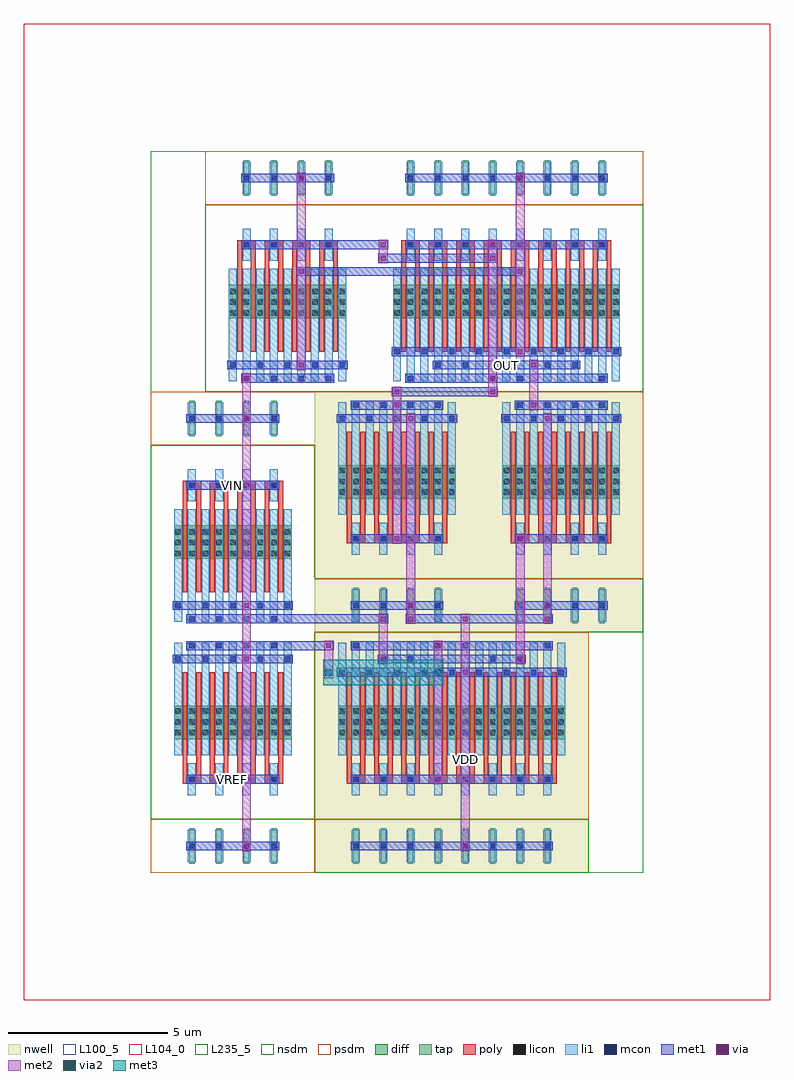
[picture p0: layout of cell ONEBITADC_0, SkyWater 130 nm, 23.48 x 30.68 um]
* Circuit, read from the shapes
.subckt ONEBITADC_0 OUT VDD VIN VREF
XM1 n1 VREF VSUBS VSUBS sky130_fd_pr__nfet_01v8 w=1.05 l=0.15 m=8
XM2 n2 VIN VSUBS VSUBS sky130_fd_pr__nfet_01v8 w=1.05 l=0.15 m=8
XM3 VSUBS n3 VSUBS VSUBS sky130_fd_pr__nfet_01v8 w=1.05 l=0.15 m=8
XM4 n3 n3 VSUBS VSUBS sky130_fd_pr__nfet_01v8 w=1.05 l=0.15 m=8
XM5 OUT n3 VSUBS VSUBS sky130_fd_pr__nfet_01v8 w=1.05 l=0.15 m=8
XM6 n1 n1 VDD VDD sky130_fd_pr__pfet_01v8 w=1.05 l=0.15 m=8
XM7 n3 n3 VDD VDD sky130_fd_pr__pfet_01v8 w=1.05 l=0.15 m=8
XM8 n2 n1 VDD VDD sky130_fd_pr__pfet_01v8 w=1.05 l=0.15 m=8
XM9 OUT n2 VDD VDD sky130_fd_pr__pfet_01v8 w=1.05 l=0.15 m=8
.ends

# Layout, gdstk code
from math import pi, radians
import gdstk
lib = gdstk.Library(unit=1e-6, precision=1e-09)
def R(c, l, rs):  # rectangles x0, y0, x1, y1
    for r in rs: c.add(gdstk.rectangle(r[:2], r[2:], *l))
def A(c, l, x, y, w, h, nx, ny, dx, dy):  # array of equal rectangles
    R(c, l, [(x+i*dx, y+j*dy, x+i*dx+w, y+j*dy+h) for i in range(nx) for j in range(ny)])
def P(c, l, *ps):  # polygons
    for p in ps: c.add(gdstk.Polygon(p, *l))
nwell = (64, 20)
diff = (65, 20)
tap = (65, 44)
poly = (66, 20)
licon = (66, 44)
li1 = (67, 20)
mcon = (67, 44)
met1 = (68, 20)
via = (68, 44)
met2 = (69, 20)
via2 = (69, 44)
met3 = (70, 20)
nsdm = (93, 44)
psdm = (94, 20)
L100_5 = (100, 5)
L104_0 = (104, 0)
L235_5 = (235, 5)

scm_nmos_38434623_x4_y1_ = lib.new_cell('SCM_NMOS_38434623_X4_Y1_1678970416_1678970418')
R(scm_nmos_38434623_x4_y1_, diff, [(0.735,2.31,7.865,3.36)])
A(scm_nmos_38434623_x4_y1_, tap, 1.205, 6.16, 0.17, 1.12, 8, 1, 0.86, 0)
A(scm_nmos_38434623_x4_y1_, poly, 1, 1.26, 0.15, 3.36, 16, 1, 0.43, 0)
A(scm_nmos_38434623_x4_y1_, poly, 1, 4.485, 0.58, 0.27, 8, 1, 0.86, 0)
A(scm_nmos_38434623_x4_y1_, licon, 0.775, 2.39, 0.17, 0.17, 3, 3, 0.43, 0.34)
A(scm_nmos_38434623_x4_y1_, licon, 1.635, 2.39, 0.17, 0.17, 3, 3, 0.43, 0.34)
A(scm_nmos_38434623_x4_y1_, licon, 2.495, 2.39, 0.17, 0.17, 3, 3, 0.43, 0.34)
A(scm_nmos_38434623_x4_y1_, licon, 3.355, 2.39, 0.17, 0.17, 3, 3, 0.43, 0.34)
A(scm_nmos_38434623_x4_y1_, licon, 4.215, 2.39, 0.17, 0.17, 3, 3, 0.43, 0.34)
A(scm_nmos_38434623_x4_y1_, licon, 5.075, 2.39, 0.17, 0.17, 3, 3, 0.43, 0.34)
A(scm_nmos_38434623_x4_y1_, licon, 5.935, 2.39, 0.17, 0.17, 3, 3, 0.43, 0.34)
A(scm_nmos_38434623_x4_y1_, licon, 6.795, 2.39, 0.17, 0.17, 3, 3, 0.43, 0.34)
A(scm_nmos_38434623_x4_y1_, licon, 1.205, 4.535, 0.17, 0.17, 8, 2, 0.86, 2.1)
A(scm_nmos_38434623_x4_y1_, li1, 0.735, 0.335, 0.25, 3.53, 17, 1, 0.43, 0)
A(scm_nmos_38434623_x4_y1_, li1, 1.165, 4.115, 0.25, 1.01, 8, 2, 0.86, 2.1)
A(scm_nmos_38434623_x4_y1_, mcon, 0.775, 1.175, 0.17, 0.17, 9, 1, 0.86, 0)
A(scm_nmos_38434623_x4_y1_, mcon, 1.205, 4.535, 0.17, 0.17, 8, 2, 0.86, 2.1)
R(scm_nmos_38434623_x4_y1_, mcon, [(1.205,0.335,1.375,0.505), (3.785,0.335,3.955,0.505), (4.645,0.335,4.815,0.505), (7.225,0.335,7.395,0.505), (2.065,0.755,2.235,0.925), (2.925,0.755,3.095,0.925), (5.505,0.755,5.675,0.925), (6.365,0.755,6.535,0.925)])
R(scm_nmos_38434623_x4_y1_, met1, [(1.12,0.28,7.48,0.56), (1.98,0.7,6.62,0.98), (0.69,1.12,7.91,1.4), (1.12,4.48,7.48,4.76), (1.12,6.58,7.48,6.86)])
R(scm_nmos_38434623_x4_y1_, via, [(3.795,0.345,3.945,0.495), (4.655,1.185,4.805,1.335), (3.795,4.545,3.945,4.695), (4.655,6.645,4.805,6.795)])
R(scm_nmos_38434623_x4_y1_, met2, [(3.73,0.26,4.01,4.78), (4.59,1.1,4.87,6.88)])
R(scm_nmos_38434623_x4_y1_, nsdm, [(0,0,8.6,5.88)])
R(scm_nmos_38434623_x4_y1_, psdm, [(0,5.88,8.6,7.56)])
R(scm_nmos_38434623_x4_y1_, L100_5, [(0,0,8.6,7.56)])

nmos_s_93094360_x4_y1_16 = lib.new_cell('NMOS_S_93094360_X4_Y1_1678970415_1678970418')
R(nmos_s_93094360_x4_y1_16, diff, [(0.735,2.31,4.425,3.36)])
A(nmos_s_93094360_x4_y1_16, tap, 1.205, 6.16, 0.17, 1.12, 4, 1, 0.86, 0)
A(nmos_s_93094360_x4_y1_16, poly, 1, 1.26, 0.15, 3.36, 8, 1, 0.43, 0)
A(nmos_s_93094360_x4_y1_16, poly, 1, 4.485, 0.58, 0.27, 4, 1, 0.86, 0)
A(nmos_s_93094360_x4_y1_16, licon, 0.775, 2.39, 0.17, 0.17, 3, 3, 0.43, 0.34)
A(nmos_s_93094360_x4_y1_16, licon, 1.635, 2.39, 0.17, 0.17, 3, 3, 0.43, 0.34)
A(nmos_s_93094360_x4_y1_16, licon, 2.495, 2.39, 0.17, 0.17, 3, 3, 0.43, 0.34)
A(nmos_s_93094360_x4_y1_16, licon, 3.355, 2.39, 0.17, 0.17, 3, 3, 0.43, 0.34)
A(nmos_s_93094360_x4_y1_16, licon, 1.205, 4.535, 0.17, 0.17, 4, 2, 0.86, 2.1)
A(nmos_s_93094360_x4_y1_16, li1, 0.735, 0.335, 0.25, 3.53, 9, 1, 0.43, 0)
A(nmos_s_93094360_x4_y1_16, li1, 1.165, 4.115, 0.25, 1.01, 4, 2, 0.86, 2.1)
A(nmos_s_93094360_x4_y1_16, mcon, 1.205, 0.335, 0.17, 0.17, 4, 2, 0.86, 4.2)
A(nmos_s_93094360_x4_y1_16, mcon, 0.775, 0.755, 0.17, 0.17, 5, 1, 0.86, 0)
A(nmos_s_93094360_x4_y1_16, mcon, 1.205, 6.635, 0.17, 0.17, 4, 1, 0.86, 0)
R(nmos_s_93094360_x4_y1_16, met1, [(1.12,0.28,4.04,0.56), (0.69,0.7,4.47,0.98), (1.12,4.48,4.04,4.76), (1.12,6.58,4.04,6.86)])
R(nmos_s_93094360_x4_y1_16, via, [(2.935,0.765,3.085,0.915), (2.935,6.645,3.085,6.795)])
R(nmos_s_93094360_x4_y1_16, met2, [(2.87,0.68,3.15,6.88)])
R(nmos_s_93094360_x4_y1_16, nsdm, [(0,0,5.16,5.88)])
R(nmos_s_93094360_x4_y1_16, psdm, [(0,5.88,5.16,7.56)])
R(nmos_s_93094360_x4_y1_16, L100_5, [(0,0,5.16,7.56)])

cmb_nmos_2_93363889_0_0_ = lib.new_cell('CMB_NMOS_2_93363889_0_0_1678970418')
R(cmb_nmos_2_93363889_0_0_, met1, [(2.85,3.64,3.17,3.92), (2.85,3.64,3.17,3.92), (3.01,3.64,9.89,3.92), (9.73,3.64,10.05,3.92), (9.73,3.64,10.05,3.92), (5.43,4.06,5.75,4.34), (5.43,4.06,5.75,4.34), (5.59,4.06,9.03,4.34), (8.87,4.06,9.19,4.34), (8.87,4.06,9.19,4.34), (3.87,4.48,5.59,4.76), (5.43,4.48,5.75,4.76), (5.43,4.48,5.75,4.76)])
P(cmb_nmos_2_93363889_0_0_, met1, [(0,0),(0,0),(0,0),(0,0)],
  [(0,0),(0,0),(0,0),(0,0)],
  [(0,0),(0,0),(0,0),(0,0)])
R(cmb_nmos_2_93363889_0_0_, via, [(2.935,3.705,3.085,3.855), (2.935,3.705,3.085,3.855), (9.815,3.705,9.965,3.855), (9.815,3.705,9.965,3.855), (5.515,4.125,5.665,4.275), (5.515,4.125,5.665,4.275), (8.955,4.125,9.105,4.275), (8.955,4.125,9.105,4.275), (5.515,4.545,5.665,4.695), (5.515,4.545,5.665,4.695)])
R(cmb_nmos_2_93363889_0_0_, met2, [(2.87,3.62,3.15,3.94), (2.87,3.62,3.15,3.94), (9.75,3.62,10.03,3.94), (9.75,3.62,10.03,3.94), (5.45,4.04,5.73,4.36), (5.45,4.04,5.73,4.36), (8.89,4.04,9.17,4.36), (8.89,4.04,9.17,4.36), (5.45,4.2,5.73,4.62), (5.45,4.46,5.73,4.78), (5.45,4.46,5.73,4.78)])
P(cmb_nmos_2_93363889_0_0_, met2, [(0,0),(0,0),(0,0),(0,0)],
  [(0,0),(0,0),(0,0),(0,0)],
  [(0,0),(0,0),(0,0),(0,0)])
R(cmb_nmos_2_93363889_0_0_, L235_5, [(0,0,13.76,7.56)])
cmb_nmos_2_93363889_0_0_.add(gdstk.Reference(scm_nmos_38434623_x4_y1_, (5.16,0)))
cmb_nmos_2_93363889_0_0_.add(gdstk.Reference(nmos_s_93094360_x4_y1_16, (0,0)))

scm_pmos_25290471_x4_y1_ = lib.new_cell('SCM_PMOS_25290471_X4_Y1_1678970423')
R(scm_pmos_25290471_x4_y1_, nwell, [(0,0,8.6,7.56)])
R(scm_pmos_25290471_x4_y1_, diff, [(0.735,2.31,7.865,3.36)])
A(scm_pmos_25290471_x4_y1_, tap, 1.205, 6.16, 0.17, 1.12, 8, 1, 0.86, 0)
A(scm_pmos_25290471_x4_y1_, poly, 1, 1.26, 0.15, 3.36, 16, 1, 0.43, 0)
A(scm_pmos_25290471_x4_y1_, poly, 1, 4.485, 0.58, 0.27, 8, 1, 0.86, 0)
A(scm_pmos_25290471_x4_y1_, licon, 0.775, 2.39, 0.17, 0.17, 3, 3, 0.43, 0.34)
A(scm_pmos_25290471_x4_y1_, licon, 1.635, 2.39, 0.17, 0.17, 3, 3, 0.43, 0.34)
A(scm_pmos_25290471_x4_y1_, licon, 2.495, 2.39, 0.17, 0.17, 3, 3, 0.43, 0.34)
A(scm_pmos_25290471_x4_y1_, licon, 3.355, 2.39, 0.17, 0.17, 3, 3, 0.43, 0.34)
A(scm_pmos_25290471_x4_y1_, licon, 4.215, 2.39, 0.17, 0.17, 3, 3, 0.43, 0.34)
A(scm_pmos_25290471_x4_y1_, licon, 5.075, 2.39, 0.17, 0.17, 3, 3, 0.43, 0.34)
A(scm_pmos_25290471_x4_y1_, licon, 5.935, 2.39, 0.17, 0.17, 3, 3, 0.43, 0.34)
A(scm_pmos_25290471_x4_y1_, licon, 6.795, 2.39, 0.17, 0.17, 3, 3, 0.43, 0.34)
A(scm_pmos_25290471_x4_y1_, licon, 1.205, 4.535, 0.17, 0.17, 8, 2, 0.86, 2.1)
A(scm_pmos_25290471_x4_y1_, li1, 0.735, 0.335, 0.25, 3.53, 17, 1, 0.43, 0)
A(scm_pmos_25290471_x4_y1_, li1, 1.165, 4.115, 0.25, 1.01, 8, 2, 0.86, 2.1)
A(scm_pmos_25290471_x4_y1_, mcon, 0.775, 1.175, 0.17, 0.17, 9, 1, 0.86, 0)
A(scm_pmos_25290471_x4_y1_, mcon, 1.205, 4.535, 0.17, 0.17, 8, 2, 0.86, 2.1)
R(scm_pmos_25290471_x4_y1_, mcon, [(1.205,0.335,1.375,0.505), (3.785,0.335,3.955,0.505), (4.645,0.335,4.815,0.505), (7.225,0.335,7.395,0.505), (2.065,0.755,2.235,0.925), (2.925,0.755,3.095,0.925), (5.505,0.755,5.675,0.925), (6.365,0.755,6.535,0.925)])
R(scm_pmos_25290471_x4_y1_, met1, [(1.12,0.28,7.48,0.56), (1.98,0.7,6.62,0.98), (0.69,1.12,7.91,1.4), (1.12,4.48,7.48,4.76), (1.12,6.58,7.48,6.86)])
R(scm_pmos_25290471_x4_y1_, via, [(3.795,0.345,3.945,0.495), (4.655,1.185,4.805,1.335), (3.795,4.545,3.945,4.695), (4.655,6.645,4.805,6.795)])
R(scm_pmos_25290471_x4_y1_, met2, [(3.73,0.26,4.01,4.78), (4.59,1.1,4.87,6.88)])
R(scm_pmos_25290471_x4_y1_, nsdm, [(0,5.88,8.6,7.56)])
R(scm_pmos_25290471_x4_y1_, psdm, [(0,0,8.6,5.88)])
R(scm_pmos_25290471_x4_y1_, L100_5, [(0,0,8.6,7.56)])

dcl_pmos_s_3785225_x4_y1 = lib.new_cell('DCL_PMOS_S_3785225_X4_Y1_1678970419')
R(dcl_pmos_s_3785225_x4_y1, nwell, [(0,0,5.16,7.56)])
R(dcl_pmos_s_3785225_x4_y1, diff, [(0.735,2.31,4.425,3.36)])
A(dcl_pmos_s_3785225_x4_y1, tap, 1.205, 6.16, 0.17, 1.12, 4, 1, 0.86, 0)
A(dcl_pmos_s_3785225_x4_y1, poly, 1, 1.26, 0.15, 3.36, 8, 1, 0.43, 0)
A(dcl_pmos_s_3785225_x4_y1, poly, 1, 4.485, 0.58, 0.27, 4, 1, 0.86, 0)
A(dcl_pmos_s_3785225_x4_y1, licon, 0.775, 2.39, 0.17, 0.17, 3, 3, 0.43, 0.34)
A(dcl_pmos_s_3785225_x4_y1, licon, 1.635, 2.39, 0.17, 0.17, 3, 3, 0.43, 0.34)
A(dcl_pmos_s_3785225_x4_y1, licon, 2.495, 2.39, 0.17, 0.17, 3, 3, 0.43, 0.34)
A(dcl_pmos_s_3785225_x4_y1, licon, 3.355, 2.39, 0.17, 0.17, 3, 3, 0.43, 0.34)
A(dcl_pmos_s_3785225_x4_y1, licon, 1.205, 4.535, 0.17, 0.17, 4, 2, 0.86, 2.1)
A(dcl_pmos_s_3785225_x4_y1, li1, 0.735, 0.335, 0.25, 3.53, 9, 1, 0.43, 0)
A(dcl_pmos_s_3785225_x4_y1, li1, 1.165, 4.115, 0.25, 1.01, 4, 2, 0.86, 2.1)
A(dcl_pmos_s_3785225_x4_y1, mcon, 1.205, 0.335, 0.17, 0.17, 4, 2, 0.86, 4.2)
A(dcl_pmos_s_3785225_x4_y1, mcon, 0.775, 0.755, 0.17, 0.17, 5, 1, 0.86, 0)
A(dcl_pmos_s_3785225_x4_y1, mcon, 1.205, 6.635, 0.17, 0.17, 4, 1, 0.86, 0)
R(dcl_pmos_s_3785225_x4_y1, met1, [(1.12,0.28,4.04,0.56), (0.69,0.7,4.47,0.98), (1.12,4.48,4.04,4.76), (1.12,6.58,4.04,6.86)])
R(dcl_pmos_s_3785225_x4_y1, via, [(2.505,0.345,2.655,0.495), (2.935,0.765,3.085,0.915), (2.505,4.545,2.655,4.695), (2.935,6.645,3.085,6.795)])
R(dcl_pmos_s_3785225_x4_y1, met2, [(2.44,0.26,2.72,4.78), (2.87,0.68,3.15,6.88)])
R(dcl_pmos_s_3785225_x4_y1, nsdm, [(0,5.88,5.16,7.56)])
R(dcl_pmos_s_3785225_x4_y1, psdm, [(0,0,5.16,5.88)])
R(dcl_pmos_s_3785225_x4_y1, L100_5, [(0,0,5.16,7.56)])

c_nmos_s_93094360_x4_y1_16 = lib.new_cell('NMOS_S_93094360_X4_Y1_1678970421')
R(c_nmos_s_93094360_x4_y1_16, diff, [(0.735,2.31,4.425,3.36)])
A(c_nmos_s_93094360_x4_y1_16, tap, 1.205, 6.16, 0.17, 1.12, 4, 1, 0.86, 0)
A(c_nmos_s_93094360_x4_y1_16, poly, 1, 1.26, 0.15, 3.36, 8, 1, 0.43, 0)
A(c_nmos_s_93094360_x4_y1_16, poly, 1, 4.485, 0.58, 0.27, 4, 1, 0.86, 0)
A(c_nmos_s_93094360_x4_y1_16, licon, 0.775, 2.39, 0.17, 0.17, 3, 3, 0.43, 0.34)
A(c_nmos_s_93094360_x4_y1_16, licon, 1.635, 2.39, 0.17, 0.17, 3, 3, 0.43, 0.34)
A(c_nmos_s_93094360_x4_y1_16, licon, 2.495, 2.39, 0.17, 0.17, 3, 3, 0.43, 0.34)
A(c_nmos_s_93094360_x4_y1_16, licon, 3.355, 2.39, 0.17, 0.17, 3, 3, 0.43, 0.34)
A(c_nmos_s_93094360_x4_y1_16, licon, 1.205, 4.535, 0.17, 0.17, 4, 2, 0.86, 2.1)
A(c_nmos_s_93094360_x4_y1_16, li1, 0.735, 0.335, 0.25, 3.53, 9, 1, 0.43, 0)
A(c_nmos_s_93094360_x4_y1_16, li1, 1.165, 4.115, 0.25, 1.01, 4, 2, 0.86, 2.1)
A(c_nmos_s_93094360_x4_y1_16, mcon, 1.205, 0.335, 0.17, 0.17, 4, 2, 0.86, 4.2)
A(c_nmos_s_93094360_x4_y1_16, mcon, 0.775, 0.755, 0.17, 0.17, 5, 1, 0.86, 0)
A(c_nmos_s_93094360_x4_y1_16, mcon, 1.205, 6.635, 0.17, 0.17, 4, 1, 0.86, 0)
R(c_nmos_s_93094360_x4_y1_16, met1, [(1.12,0.28,4.04,0.56), (0.69,0.7,4.47,0.98), (1.12,4.48,4.04,4.76), (1.12,6.58,4.04,6.86)])
R(c_nmos_s_93094360_x4_y1_16, via, [(2.935,0.765,3.085,0.915), (2.935,6.645,3.085,6.795)])
R(c_nmos_s_93094360_x4_y1_16, met2, [(2.87,0.68,3.15,6.88)])
R(c_nmos_s_93094360_x4_y1_16, nsdm, [(0,0,5.16,5.88)])
R(c_nmos_s_93094360_x4_y1_16, psdm, [(0,5.88,5.16,7.56)])
R(c_nmos_s_93094360_x4_y1_16, L100_5, [(0,0,5.16,7.56)])

nmos_s_78993529_x4_y1_16 = lib.new_cell('NMOS_S_78993529_X4_Y1_1678970420')
R(nmos_s_78993529_x4_y1_16, diff, [(0.735,2.31,4.425,3.36)])
A(nmos_s_78993529_x4_y1_16, tap, 1.205, 6.16, 0.17, 1.12, 4, 1, 0.86, 0)
A(nmos_s_78993529_x4_y1_16, poly, 1, 1.26, 0.15, 3.36, 8, 1, 0.43, 0)
A(nmos_s_78993529_x4_y1_16, poly, 1, 4.485, 0.58, 0.27, 4, 1, 0.86, 0)
A(nmos_s_78993529_x4_y1_16, licon, 0.775, 2.39, 0.17, 0.17, 3, 3, 0.43, 0.34)
A(nmos_s_78993529_x4_y1_16, licon, 1.635, 2.39, 0.17, 0.17, 3, 3, 0.43, 0.34)
A(nmos_s_78993529_x4_y1_16, licon, 2.495, 2.39, 0.17, 0.17, 3, 3, 0.43, 0.34)
A(nmos_s_78993529_x4_y1_16, licon, 3.355, 2.39, 0.17, 0.17, 3, 3, 0.43, 0.34)
A(nmos_s_78993529_x4_y1_16, licon, 1.205, 4.535, 0.17, 0.17, 4, 2, 0.86, 2.1)
A(nmos_s_78993529_x4_y1_16, li1, 0.735, 0.335, 0.25, 3.53, 9, 1, 0.43, 0)
A(nmos_s_78993529_x4_y1_16, li1, 1.165, 4.115, 0.25, 1.01, 4, 2, 0.86, 2.1)
A(nmos_s_78993529_x4_y1_16, mcon, 1.205, 0.335, 0.17, 0.17, 4, 2, 0.86, 4.2)
A(nmos_s_78993529_x4_y1_16, mcon, 0.775, 0.755, 0.17, 0.17, 5, 1, 0.86, 0)
A(nmos_s_78993529_x4_y1_16, mcon, 1.205, 6.635, 0.17, 0.17, 4, 1, 0.86, 0)
R(nmos_s_78993529_x4_y1_16, met1, [(1.12,0.28,4.04,0.56), (0.69,0.7,4.47,0.98), (1.12,4.48,4.04,4.76), (1.12,6.58,4.04,6.86)])
R(nmos_s_78993529_x4_y1_16, via, [(2.935,0.765,3.085,0.915), (2.935,6.645,3.085,6.795)])
R(nmos_s_78993529_x4_y1_16, met2, [(2.87,0.68,3.15,6.88)])
R(nmos_s_78993529_x4_y1_16, nsdm, [(0,0,5.16,5.88)])
R(nmos_s_78993529_x4_y1_16, psdm, [(0,5.88,5.16,7.56)])
R(nmos_s_78993529_x4_y1_16, L100_5, [(0,0,5.16,7.56)])

pmos_s_59912959_x4_y1_16 = lib.new_cell('PMOS_S_59912959_X4_Y1_1678970422')
R(pmos_s_59912959_x4_y1_16, nwell, [(0,0,5.16,7.56)])
R(pmos_s_59912959_x4_y1_16, diff, [(0.735,2.31,4.425,3.36)])
A(pmos_s_59912959_x4_y1_16, tap, 1.205, 6.16, 0.17, 1.12, 4, 1, 0.86, 0)
A(pmos_s_59912959_x4_y1_16, poly, 1, 1.26, 0.15, 3.36, 8, 1, 0.43, 0)
A(pmos_s_59912959_x4_y1_16, poly, 1, 4.485, 0.58, 0.27, 4, 1, 0.86, 0)
A(pmos_s_59912959_x4_y1_16, licon, 0.775, 2.39, 0.17, 0.17, 3, 3, 0.43, 0.34)
A(pmos_s_59912959_x4_y1_16, licon, 1.635, 2.39, 0.17, 0.17, 3, 3, 0.43, 0.34)
A(pmos_s_59912959_x4_y1_16, licon, 2.495, 2.39, 0.17, 0.17, 3, 3, 0.43, 0.34)
A(pmos_s_59912959_x4_y1_16, licon, 3.355, 2.39, 0.17, 0.17, 3, 3, 0.43, 0.34)
A(pmos_s_59912959_x4_y1_16, licon, 1.205, 4.535, 0.17, 0.17, 4, 2, 0.86, 2.1)
A(pmos_s_59912959_x4_y1_16, li1, 0.735, 0.335, 0.25, 3.53, 9, 1, 0.43, 0)
A(pmos_s_59912959_x4_y1_16, li1, 1.165, 4.115, 0.25, 1.01, 4, 2, 0.86, 2.1)
A(pmos_s_59912959_x4_y1_16, mcon, 1.205, 0.335, 0.17, 0.17, 4, 2, 0.86, 4.2)
A(pmos_s_59912959_x4_y1_16, mcon, 0.775, 0.755, 0.17, 0.17, 5, 1, 0.86, 0)
A(pmos_s_59912959_x4_y1_16, mcon, 1.205, 6.635, 0.17, 0.17, 4, 1, 0.86, 0)
R(pmos_s_59912959_x4_y1_16, met1, [(1.12,0.28,4.04,0.56), (0.69,0.7,4.47,0.98), (1.12,4.48,4.04,4.76), (1.12,6.58,4.04,6.86)])
R(pmos_s_59912959_x4_y1_16, via, [(2.935,0.765,3.085,0.915), (2.935,6.645,3.085,6.795)])
R(pmos_s_59912959_x4_y1_16, met2, [(2.87,0.68,3.15,6.88)])
R(pmos_s_59912959_x4_y1_16, nsdm, [(0,5.88,5.16,7.56)])
R(pmos_s_59912959_x4_y1_16, psdm, [(0,0,5.16,5.88)])
R(pmos_s_59912959_x4_y1_16, L100_5, [(0,0,5.16,7.56)])

onebitadc_0 = lib.new_cell('ONEBITADC_0')
R(onebitadc_0, met1, [(7.15,6.58,7.47,6.86), (7.15,6.58,7.47,6.86), (7.15,6.58,7.47,6.86), (7.15,6.58,7.47,6.86), (11.45,6.58,11.77,6.86), (11.45,6.58,11.77,6.86), (3.87,7,5.59,7.28), (5.43,7,5.75,7.28), (5.43,7,5.75,7.28), (3.87,7.84,7.31,8.12), (7.15,7.84,7.47,8.12), (7.15,7.84,7.47,8.12), (7.15,7.84,7.47,8.12), (7.15,7.84,7.47,8.12), (8.01,7.84,8.33,8.12), (8.01,7.84,8.33,8.12), (8.01,7.84,8.33,8.12), (8.01,7.84,8.33,8.12), (8.17,7.84,9.89,8.12), (9.73,7.84,10.05,8.12), (9.73,7.84,10.05,8.12), (9.73,7.84,10.05,8.12), (9.73,7.84,10.05,8.12), (9.89,7.84,12.47,8.12), (12.31,7.84,12.63,8.12), (12.31,7.84,12.63,8.12), (11.45,10.36,11.77,10.64), (11.45,10.36,11.77,10.64), (11.88,14.56,12.2,14.84), (11.88,14.56,12.2,14.84), (7.58,14.98,7.9,15.26), (7.58,14.98,7.9,15.26), (7.74,14.98,10.75,15.26), (10.59,14.98,10.91,15.26), (10.59,14.98,10.91,15.26), (2.85,15.4,3.17,15.68), (2.85,15.4,3.17,15.68), (11.88,15.82,12.2,16.1), (11.88,15.82,12.2,16.1)])
P(onebitadc_0, met1, [(0,0),(0,0),(0,0),(0,0)],
  [(0,0),(0,0),(0,0),(0,0)],
  [(0,0),(0,0),(0,0),(0,0)],
  [(0,0),(0,0),(0,0),(0,0)],
  [(0,0),(0,0),(0,0),(0,0)],
  [(0,0),(0,0),(0,0),(0,0)],
  [(0,0),(0,0),(0,0),(0,0)],
  [(0,0),(0,0),(0,0),(0,0)],
  [(0,0),(0,0),(0,0),(0,0)],
  [(0,0),(0,0),(0,0),(0,0)],
  [(0,0),(0,0),(0,0),(0,0)],
  [(0,0),(0,0),(0,0),(0,0)],
  [(0,0),(0,0),(0,0),(0,0)],
  [(0,0),(0,0),(0,0),(0,0)],
  [(0,0),(0,0),(0,0),(0,0)],
  [(0,0),(0,0),(0,0),(0,0)])
R(onebitadc_0, via, [(7.235,6.645,7.385,6.795), (7.235,6.645,7.385,6.795), (7.235,6.645,7.385,6.795), (7.235,6.645,7.385,6.795), (11.535,6.645,11.685,6.795), (11.535,6.645,11.685,6.795), (5.515,7.065,5.665,7.215), (5.515,7.065,5.665,7.215), (7.235,7.905,7.385,8.055), (7.235,7.905,7.385,8.055), (7.235,7.905,7.385,8.055), (7.235,7.905,7.385,8.055), (8.095,7.905,8.245,8.055), (8.095,7.905,8.245,8.055), (8.095,7.905,8.245,8.055), (8.095,7.905,8.245,8.055), (9.815,7.905,9.965,8.055), (9.815,7.905,9.965,8.055), (9.815,7.905,9.965,8.055), (9.815,7.905,9.965,8.055), (12.395,7.905,12.545,8.055), (12.395,7.905,12.545,8.055), (11.535,10.425,11.685,10.575), (11.535,10.425,11.685,10.575), (11.965,14.625,12.115,14.775), (11.965,14.625,12.115,14.775), (7.665,15.045,7.815,15.195), (7.665,15.045,7.815,15.195), (10.675,15.045,10.825,15.195), (10.675,15.045,10.825,15.195), (2.935,15.465,3.085,15.615), (2.935,15.465,3.085,15.615), (11.965,15.885,12.115,16.035), (11.965,15.885,12.115,16.035)])
R(onebitadc_0, met2, [(5.45,6.115,5.73,6.485), (5.45,6.115,5.73,6.485), (8.89,6.115,9.17,6.485), (8.89,6.115,9.17,6.485), (5.45,6.3,5.73,7.14), (9.75,6.3,10.03,7.98), (7.17,6.56,7.45,6.88), (7.17,6.56,7.45,6.88), (7.17,6.56,7.45,6.88), (7.17,6.56,7.45,6.88), (11.47,6.56,11.75,6.88), (11.47,6.56,11.75,6.88), (2.87,6.72,3.15,8.4), (7.17,6.72,7.45,7.98), (11.47,6.72,11.75,10.5), (5.45,6.98,5.73,7.3), (5.45,6.98,5.73,7.3), (7.17,7.82,7.45,8.14), (7.17,7.82,7.45,8.14), (7.17,7.82,7.45,8.14), (7.17,7.82,7.45,8.14), (8.03,7.82,8.31,8.14), (8.03,7.82,8.31,8.14), (8.03,7.82,8.31,8.14), (8.03,7.82,8.31,8.14), (9.75,7.82,10.03,8.14), (9.75,7.82,10.03,8.14), (9.75,7.82,10.03,8.14), (9.75,7.82,10.03,8.14), (12.33,7.82,12.61,8.14), (12.33,7.82,12.61,8.14), (8.03,7.98,8.31,8.4), (12.33,7.98,12.61,8.4), (11.47,10.34,11.75,10.66), (11.47,10.34,11.75,10.66), (2.87,14.28,3.15,15.54), (11.9,14.54,12.18,14.86), (11.9,14.54,12.18,14.86), (7.6,14.7,7.88,15.12), (11.9,14.7,12.18,15.96), (7.6,14.96,7.88,15.28), (7.6,14.96,7.88,15.28), (10.61,14.96,10.89,15.28), (10.61,14.96,10.89,15.28), (10.61,15.12,10.89,15.54), (2.87,15.38,3.15,15.7), (2.87,15.38,3.15,15.7), (11.9,15.8,12.18,16.12), (11.9,15.8,12.18,16.12)])
P(onebitadc_0, met2, [(0,0),(0,0),(0,0),(0,0)],
  [(0,0),(0,0),(0,0),(0,0)],
  [(0,0),(0,0),(0,0),(0,0)],
  [(0,0),(0,0),(0,0),(0,0)],
  [(0,0),(0,0),(0,0),(0,0)],
  [(0,0),(0,0),(0,0),(0,0)],
  [(0,0),(0,0),(0,0),(0,0)],
  [(0,0),(0,0),(0,0),(0,0)],
  [(0,0),(0,0),(0,0),(0,0)],
  [(0,0),(0,0),(0,0),(0,0)],
  [(0,0),(0,0),(0,0),(0,0)],
  [(0,0),(0,0),(0,0),(0,0)],
  [(0,0),(0,0),(0,0),(0,0)],
  [(0,0),(0,0),(0,0),(0,0)],
  [(0,0),(0,0),(0,0),(0,0)])
R(onebitadc_0, via2, [(5.49,6.2,5.69,6.4), (5.49,6.2,5.69,6.4), (8.93,6.2,9.13,6.4), (8.93,6.2,9.13,6.4)])
R(onebitadc_0, met3, [(5.425,5.9,5.755,6.7), (5.425,5.9,5.755,6.7), (5.59,5.9,9.03,6.7), (8.865,5.9,9.195,6.7), (8.865,5.9,9.195,6.7)])
R(onebitadc_0, L104_0, [(-4,-4,19.48,26.68)])
R(onebitadc_0, L235_5, [(0,0,15.48,22.68)])
onebitadc_0.add(gdstk.Reference(cmb_nmos_2_93363889_0_0_, (1.72,15.12)))
onebitadc_0.add(gdstk.Reference(scm_pmos_25290471_x4_y1_, (5.16,7.56), x_reflection=True))
onebitadc_0.add(gdstk.Reference(dcl_pmos_s_3785225_x4_y1, (5.16,15.12), x_reflection=True))
onebitadc_0.add(gdstk.Reference(c_nmos_s_93094360_x4_y1_16, (0,7.56)))
onebitadc_0.add(gdstk.Reference(nmos_s_78993529_x4_y1_16, (0,7.56), x_reflection=True))
onebitadc_0.add(gdstk.Reference(pmos_s_59912959_x4_y1_16, (15.48,15.12), rotation=pi))
onebitadc_0.add(gdstk.Label('OUT', (11.18,15.96), layer=68, texttype=5))
onebitadc_0.add(gdstk.Label('VDD', (9.89,3.57), layer=69, texttype=5))
onebitadc_0.add(gdstk.Label('VIN', (2.58,12.18), layer=68, texttype=5))
onebitadc_0.add(gdstk.Label('VREF', (2.58,2.94), layer=68, texttype=5))

lib.write_gds('ONEBITADC_0.gds')
